VERSION 5.7 ;
  NOWIREEXTENSIONATPIN ON ;
  DIVIDERCHAR "/" ;
  BUSBITCHARS "[]" ;
MACRO sky130_fd_pr__cap_mim_m3_1_RRZ644
  CLASS BLOCK ;
  FOREIGN sky130_fd_pr__cap_mim_m3_1_RRZ644 ;
  ORIGIN 4.750 4.500 ;
  SIZE 9.000 BY 9.000 ;
  OBS
      LAYER met3 ;
        RECT -4.750 -4.500 4.250 4.500 ;
      LAYER met4 ;
        RECT -4.055 -3.805 3.555 3.805 ;
  END
END sky130_fd_pr__cap_mim_m3_1_RRZ644
MACRO sky130_fd_pr__cap_mim_m3_1_4CW8F2
  CLASS BLOCK ;
  FOREIGN sky130_fd_pr__cap_mim_m3_1_4CW8F2 ;
  ORIGIN 4.750 2.500 ;
  SIZE 9.000 BY 5.000 ;
  OBS
      LAYER met3 ;
        RECT -4.750 -2.500 4.250 2.500 ;
      LAYER met4 ;
        RECT -4.055 -1.805 3.555 1.805 ;
  END
END sky130_fd_pr__cap_mim_m3_1_4CW8F2
MACRO INV_B_13409687_0_1653520173
  CLASS BLOCK ;
  FOREIGN INV_B_13409687_0_1653520173 ;
  ORIGIN 0.000 0.000 ;
  SIZE 5.415 BY 7.560 ;
  OBS
      LAYER nwell ;
        RECT 0.000 0.000 3.440 7.560 ;
      LAYER pwell ;
        RECT 4.515 6.030 4.945 7.410 ;
        RECT 4.045 2.495 5.415 3.175 ;
      LAYER li1 ;
        RECT 1.165 6.215 1.415 7.225 ;
        RECT 2.025 6.215 2.275 7.225 ;
        RECT 4.605 6.215 4.855 7.225 ;
        RECT 1.165 4.115 1.415 5.125 ;
        RECT 2.025 4.115 2.275 5.125 ;
        RECT 4.605 4.115 4.855 5.125 ;
        RECT 0.735 0.335 0.985 3.865 ;
        RECT 1.165 0.335 1.415 3.865 ;
        RECT 1.595 0.335 1.845 3.865 ;
        RECT 2.025 0.335 2.275 3.865 ;
        RECT 2.455 0.335 2.705 3.865 ;
        RECT 4.175 0.335 4.425 3.865 ;
        RECT 4.605 0.335 4.855 3.865 ;
        RECT 5.035 0.335 5.285 3.865 ;
      LAYER mcon ;
        RECT 1.205 6.635 1.375 6.805 ;
        RECT 2.065 6.635 2.235 6.805 ;
        RECT 4.645 6.635 4.815 6.805 ;
        RECT 1.205 4.535 1.375 4.705 ;
        RECT 2.065 4.535 2.235 4.705 ;
        RECT 4.645 4.535 4.815 4.705 ;
        RECT 0.775 0.755 0.945 0.925 ;
        RECT 1.205 0.335 1.375 0.505 ;
        RECT 1.635 0.755 1.805 0.925 ;
        RECT 2.065 0.335 2.235 0.505 ;
        RECT 2.495 0.755 2.665 0.925 ;
        RECT 4.215 0.755 4.385 0.925 ;
        RECT 4.645 0.335 4.815 0.505 ;
        RECT 5.075 0.755 5.245 0.925 ;
      LAYER met1 ;
        RECT 1.120 6.580 2.320 6.860 ;
        RECT 4.130 6.580 5.330 6.860 ;
        RECT 1.120 4.480 4.900 4.760 ;
        RECT 0.690 0.700 2.750 0.980 ;
        RECT 4.130 0.700 5.330 0.980 ;
        RECT 1.120 0.280 4.900 0.560 ;
      LAYER via ;
        RECT 5.030 6.590 5.290 6.850 ;
        RECT 5.030 0.710 5.290 0.970 ;
      LAYER met2 ;
        RECT 5.020 0.680 5.300 6.880 ;
  END
END INV_B_13409687_0_1653520173
MACRO sky130_fd_pr__cap_mim_m3_1_F8PC2Z
  CLASS BLOCK ;
  FOREIGN sky130_fd_pr__cap_mim_m3_1_F8PC2Z ;
  ORIGIN 2.750 1.500 ;
  SIZE 5.000 BY 3.000 ;
  OBS
      LAYER met3 ;
        RECT -2.750 -1.500 2.250 1.500 ;
      LAYER met4 ;
        RECT -2.055 -0.805 1.555 0.805 ;
  END
END sky130_fd_pr__cap_mim_m3_1_F8PC2Z
MACRO sky130_fd_pr__cap_mim_m3_1_K8PL49$1
  CLASS BLOCK ;
  FOREIGN sky130_fd_pr__cap_mim_m3_1_K8PL49$1 ;
  ORIGIN 2.750 2.500 ;
  SIZE 5.000 BY 5.000 ;
  OBS
      LAYER met3 ;
        RECT -2.750 -2.500 2.250 2.500 ;
      LAYER met4 ;
        RECT -2.055 -1.805 1.555 1.805 ;
  END
END sky130_fd_pr__cap_mim_m3_1_K8PL49$1
MACRO sky130_fd_pr__cap_mim_m3_1_FJFAMD
  CLASS BLOCK ;
  FOREIGN sky130_fd_pr__cap_mim_m3_1_FJFAMD ;
  ORIGIN 1.750 1.500 ;
  SIZE 3.000 BY 3.000 ;
  OBS
      LAYER met3 ;
        RECT -1.750 -1.500 1.250 1.500 ;
      LAYER met4 ;
        RECT -1.055 -0.805 0.555 0.805 ;
  END
END sky130_fd_pr__cap_mim_m3_1_FJFAMD
MACRO sky130_fd_pr__cap_mim_m3_1_4VD94C$1
  CLASS BLOCK ;
  FOREIGN sky130_fd_pr__cap_mim_m3_1_4VD94C$1 ;
  ORIGIN 8.750 4.500 ;
  SIZE 17.000 BY 9.000 ;
  OBS
      LAYER met3 ;
        RECT -8.750 -4.500 8.250 4.500 ;
      LAYER met4 ;
        RECT -8.055 -3.805 7.555 3.805 ;
  END
END sky130_fd_pr__cap_mim_m3_1_4VD94C$1
MACRO NMOS_S_22639876_X1_Y1_1653520174
  CLASS BLOCK ;
  FOREIGN NMOS_S_22639876_X1_Y1_1653520174 ;
  ORIGIN 7.000 -0.280 ;
  SIZE 8.975 BY 7.130 ;
  OBS
      LAYER pwell ;
        RECT 1.075 6.030 1.505 7.410 ;
        RECT 0.605 2.495 1.975 3.175 ;
      LAYER li1 ;
        RECT 1.165 6.215 1.415 7.225 ;
        RECT 1.165 4.115 1.415 5.125 ;
        RECT 0.735 0.335 0.985 3.865 ;
        RECT 1.165 0.335 1.415 3.865 ;
        RECT 1.595 0.335 1.845 3.865 ;
      LAYER mcon ;
        RECT 1.205 6.635 1.375 6.805 ;
        RECT 1.205 4.535 1.375 4.705 ;
        RECT 0.775 0.755 0.945 0.925 ;
        RECT 1.205 0.335 1.375 0.505 ;
        RECT 1.635 0.755 1.805 0.925 ;
      LAYER met1 ;
        RECT 0.690 6.580 1.890 6.860 ;
        RECT -7.000 4.480 1.460 4.760 ;
        RECT 0.690 0.700 1.890 0.980 ;
        RECT 0.260 0.280 1.460 0.560 ;
      LAYER via ;
        RECT 1.590 6.590 1.850 6.850 ;
        RECT 1.590 0.710 1.850 0.970 ;
      LAYER met2 ;
        RECT 1.580 0.680 1.860 6.880 ;
  END
END NMOS_S_22639876_X1_Y1_1653520174
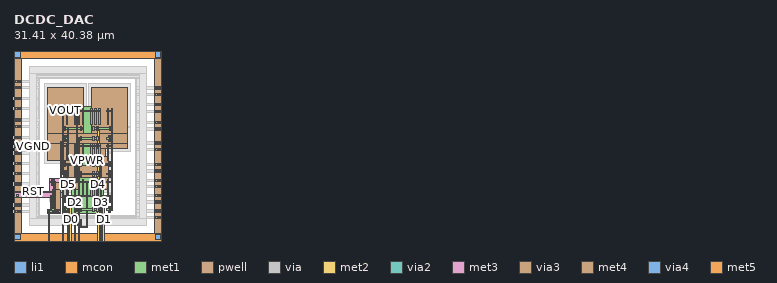
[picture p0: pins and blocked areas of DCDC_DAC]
MACRO DCDC_DAC
  CLASS BLOCK ;
  FOREIGN DCDC_DAC ;
  ORIGIN -0.080 -0.005 ;
  SIZE 31.410 BY 40.380 ;
  PIN RST
    ANTENNAGATEAREA 0.126000 ;
    PORT
      LAYER li1 ;
        RECT 8.245 9.960 8.495 10.970 ;
      LAYER mcon ;
        RECT 8.285 10.380 8.455 10.550 ;
      LAYER met1 ;
        RECT 0.080 10.325 8.540 10.605 ;
    END
  END RST
  PIN VGND
    USE GROUND ;
    PORT
      LAYER pwell ;
        RECT 10.735 21.115 11.165 22.495 ;
        RECT 20.195 21.115 20.625 22.495 ;
        RECT 10.735 13.555 11.165 14.935 ;
        RECT 20.195 13.555 20.625 14.935 ;
        RECT 8.155 11.875 8.585 13.255 ;
        RECT 10.735 5.995 11.165 7.375 ;
        RECT 20.195 5.995 20.625 7.375 ;
      LAYER li1 ;
        RECT 10.395 24.660 10.645 28.190 ;
        RECT 11.255 24.660 11.505 28.190 ;
        RECT 19.855 24.660 20.105 28.190 ;
        RECT 20.715 24.660 20.965 28.190 ;
        RECT 10.825 21.300 11.075 22.310 ;
        RECT 20.285 21.300 20.535 22.310 ;
        RECT 9.965 13.320 10.215 21.050 ;
        RECT 10.395 17.100 10.645 20.630 ;
        RECT 11.255 17.100 11.505 20.630 ;
        RECT 19.855 17.100 20.105 20.630 ;
        RECT 20.715 17.100 20.965 20.630 ;
        RECT 10.825 13.740 11.075 14.750 ;
        RECT 20.285 13.740 20.535 14.750 ;
        RECT 8.245 12.060 8.495 13.070 ;
        RECT 7.815 6.180 8.065 9.710 ;
        RECT 8.675 6.180 8.925 9.710 ;
        RECT 10.395 9.540 10.645 13.070 ;
        RECT 11.255 9.540 11.505 13.070 ;
        RECT 19.855 9.540 20.105 13.070 ;
        RECT 20.715 9.540 20.965 13.070 ;
        RECT 10.825 6.180 11.075 7.190 ;
        RECT 20.285 6.180 20.535 7.190 ;
      LAYER mcon ;
        RECT 10.435 27.600 10.605 27.770 ;
        RECT 11.295 27.600 11.465 27.770 ;
        RECT 19.895 27.600 20.065 27.770 ;
        RECT 20.755 27.600 20.925 27.770 ;
        RECT 10.865 21.720 11.035 21.890 ;
        RECT 20.325 21.720 20.495 21.890 ;
        RECT 10.005 20.880 10.175 21.050 ;
        RECT 10.005 17.100 10.175 17.270 ;
        RECT 10.435 20.040 10.605 20.210 ;
        RECT 11.295 20.040 11.465 20.210 ;
        RECT 19.895 20.040 20.065 20.210 ;
        RECT 20.755 20.040 20.925 20.210 ;
        RECT 10.865 14.160 11.035 14.330 ;
        RECT 20.325 14.160 20.495 14.330 ;
        RECT 10.005 13.320 10.175 13.490 ;
        RECT 8.285 12.480 8.455 12.650 ;
        RECT 10.435 12.480 10.605 12.650 ;
        RECT 7.855 6.600 8.025 6.770 ;
        RECT 11.295 12.480 11.465 12.650 ;
        RECT 19.895 12.480 20.065 12.650 ;
        RECT 20.755 12.480 20.925 12.650 ;
        RECT 8.715 6.600 8.885 6.770 ;
        RECT 10.865 6.600 11.035 6.770 ;
        RECT 20.325 6.600 20.495 6.770 ;
      LAYER met1 ;
        RECT 10.350 27.545 11.550 27.825 ;
        RECT 19.810 27.545 21.010 27.825 ;
        RECT 10.350 21.665 11.550 21.945 ;
        RECT 19.810 21.665 21.010 21.945 ;
        RECT 9.920 20.825 10.680 21.105 ;
        RECT 10.350 19.985 11.550 20.265 ;
        RECT 19.810 19.985 21.010 20.265 ;
        RECT 9.920 17.045 10.680 17.325 ;
        RECT 10.350 14.105 11.550 14.385 ;
        RECT 19.810 14.105 21.010 14.385 ;
        RECT 9.920 13.265 10.680 13.545 ;
        RECT 7.770 12.425 8.970 12.705 ;
        RECT 10.350 12.425 11.550 12.705 ;
        RECT 19.810 12.425 21.010 12.705 ;
        RECT 10.360 9.485 21.000 9.765 ;
        RECT 7.770 6.545 8.970 6.825 ;
        RECT 10.350 6.545 11.550 6.825 ;
        RECT 19.810 6.545 21.010 6.825 ;
      LAYER via ;
        RECT 10.390 27.555 10.650 27.815 ;
        RECT 20.710 27.555 20.970 27.815 ;
        RECT 10.390 21.675 10.650 21.935 ;
        RECT 20.710 21.675 20.970 21.935 ;
        RECT 10.390 20.835 10.650 21.095 ;
        RECT 10.390 19.995 10.650 20.255 ;
        RECT 20.710 19.995 20.970 20.255 ;
        RECT 10.390 17.055 10.650 17.315 ;
        RECT 10.390 14.115 10.650 14.375 ;
        RECT 20.710 14.115 20.970 14.375 ;
        RECT 10.390 13.275 10.650 13.535 ;
        RECT 8.670 12.435 8.930 12.695 ;
        RECT 10.390 12.435 10.650 12.695 ;
        RECT 20.710 12.435 20.970 12.695 ;
        RECT 10.390 9.495 10.650 9.755 ;
        RECT 20.710 9.495 20.970 9.755 ;
        RECT 8.670 6.555 8.930 6.815 ;
        RECT 10.390 6.555 10.650 6.815 ;
        RECT 20.710 6.555 20.970 6.815 ;
      LAYER met2 ;
        RECT 10.380 20.805 10.660 27.845 ;
        RECT 10.380 14.085 10.660 20.285 ;
        RECT 8.660 6.525 8.940 12.725 ;
        RECT 10.380 0.005 10.660 13.565 ;
        RECT 20.700 6.525 20.980 27.845 ;
      LAYER via2 ;
        RECT 8.660 9.485 8.940 9.765 ;
        RECT 10.380 9.485 10.660 9.765 ;
      LAYER met3 ;
        RECT 0.380 33.685 1.380 34.165 ;
        RECT 0.380 32.325 1.380 32.805 ;
        RECT 30.190 32.275 31.190 32.755 ;
        RECT 30.190 30.915 31.190 31.395 ;
        RECT 0.380 30.115 1.380 30.595 ;
        RECT 30.190 28.715 31.190 29.195 ;
        RECT 0.380 27.885 1.380 28.365 ;
        RECT 30.190 27.355 31.190 27.835 ;
        RECT 0.380 25.465 1.380 25.945 ;
        RECT 30.190 24.935 31.190 25.415 ;
        RECT 0.380 24.105 1.380 24.585 ;
        RECT 30.190 23.575 31.190 24.055 ;
        RECT 0.380 21.835 1.380 22.315 ;
        RECT 30.190 20.575 31.190 21.055 ;
        RECT 0.380 19.805 1.380 20.285 ;
        RECT 30.190 19.215 31.190 19.695 ;
        RECT 0.380 18.445 1.380 18.925 ;
        RECT 0.380 16.275 1.380 16.755 ;
        RECT 30.190 16.005 31.190 16.485 ;
        RECT 30.190 14.645 31.190 15.125 ;
        RECT 0.380 14.095 1.380 14.575 ;
        RECT 0.380 11.855 1.380 12.335 ;
        RECT 7.690 10.225 10.690 13.225 ;
        RECT 30.190 12.665 31.190 13.145 ;
        RECT 30.190 11.305 31.190 11.785 ;
        RECT 0.080 9.225 10.690 10.225 ;
        RECT 30.190 9.415 31.190 9.895 ;
        RECT 30.190 8.055 31.190 8.535 ;
        RECT 0.380 7.395 1.380 7.875 ;
        RECT 0.380 6.035 1.380 6.515 ;
        RECT 30.190 6.115 31.190 6.595 ;
        RECT 30.190 4.755 31.190 5.235 ;
      LAYER via3 ;
        RECT 0.490 33.770 0.810 34.090 ;
        RECT 1.010 33.770 1.330 34.090 ;
        RECT 0.490 32.410 0.810 32.730 ;
        RECT 1.010 32.410 1.330 32.730 ;
        RECT 30.240 32.360 30.560 32.680 ;
        RECT 30.760 32.360 31.080 32.680 ;
        RECT 30.240 31.000 30.560 31.320 ;
        RECT 30.760 31.000 31.080 31.320 ;
        RECT 0.490 30.200 0.810 30.520 ;
        RECT 1.010 30.200 1.330 30.520 ;
        RECT 30.240 28.800 30.560 29.120 ;
        RECT 30.760 28.800 31.080 29.120 ;
        RECT 0.490 27.970 0.810 28.290 ;
        RECT 1.010 27.970 1.330 28.290 ;
        RECT 30.240 27.440 30.560 27.760 ;
        RECT 30.760 27.440 31.080 27.760 ;
        RECT 0.490 25.550 0.810 25.870 ;
        RECT 1.010 25.550 1.330 25.870 ;
        RECT 30.240 25.020 30.560 25.340 ;
        RECT 30.760 25.020 31.080 25.340 ;
        RECT 0.490 24.190 0.810 24.510 ;
        RECT 1.010 24.190 1.330 24.510 ;
        RECT 30.240 23.660 30.560 23.980 ;
        RECT 30.760 23.660 31.080 23.980 ;
        RECT 0.490 21.920 0.810 22.240 ;
        RECT 1.010 21.920 1.330 22.240 ;
        RECT 30.240 20.660 30.560 20.980 ;
        RECT 30.760 20.660 31.080 20.980 ;
        RECT 0.490 19.880 0.810 20.200 ;
        RECT 1.010 19.880 1.330 20.200 ;
        RECT 30.240 19.300 30.560 19.620 ;
        RECT 30.760 19.300 31.080 19.620 ;
        RECT 0.490 18.520 0.810 18.840 ;
        RECT 1.010 18.520 1.330 18.840 ;
        RECT 0.490 16.360 0.810 16.680 ;
        RECT 1.010 16.360 1.330 16.680 ;
        RECT 30.240 16.090 30.560 16.410 ;
        RECT 30.760 16.090 31.080 16.410 ;
        RECT 30.240 14.730 30.560 15.050 ;
        RECT 30.760 14.730 31.080 15.050 ;
        RECT 0.490 14.180 0.810 14.500 ;
        RECT 1.010 14.180 1.330 14.500 ;
        RECT 0.490 11.940 0.810 12.260 ;
        RECT 1.010 11.940 1.330 12.260 ;
        RECT 30.240 12.750 30.560 13.070 ;
        RECT 30.760 12.750 31.080 13.070 ;
        RECT 30.240 11.390 30.560 11.710 ;
        RECT 30.760 11.390 31.080 11.710 ;
        RECT 0.620 9.470 1.140 9.990 ;
        RECT 30.240 9.500 30.560 9.820 ;
        RECT 30.760 9.500 31.080 9.820 ;
        RECT 30.240 8.140 30.560 8.460 ;
        RECT 30.760 8.140 31.080 8.460 ;
        RECT 0.490 7.480 0.810 7.800 ;
        RECT 1.010 7.480 1.330 7.800 ;
        RECT 0.490 6.120 0.810 6.440 ;
        RECT 1.010 6.120 1.330 6.440 ;
        RECT 30.240 6.200 30.560 6.520 ;
        RECT 30.760 6.200 31.080 6.520 ;
        RECT 30.240 4.840 30.560 5.160 ;
        RECT 30.760 4.840 31.080 5.160 ;
      LAYER met4 ;
        RECT 0.080 0.005 1.680 40.385 ;
        RECT 29.890 0.005 31.490 40.385 ;
      LAYER via4 ;
        RECT 0.285 39.005 1.465 40.185 ;
        RECT 0.285 0.225 1.465 1.405 ;
        RECT 30.105 39.005 31.285 40.185 ;
        RECT 30.105 0.225 31.285 1.405 ;
      LAYER met5 ;
        RECT 0.080 38.785 31.490 40.385 ;
        RECT 0.080 0.005 31.490 1.605 ;
    END
  END VGND
  PIN VPWR
    USE POWER ;
    PORT
      LAYER nwell ;
        RECT 12.240 5.845 19.120 28.525 ;
      LAYER li1 ;
        RECT 12.975 24.660 13.225 28.190 ;
        RECT 13.835 24.660 14.085 28.190 ;
        RECT 14.695 24.660 14.945 28.190 ;
        RECT 16.415 24.660 16.665 28.190 ;
        RECT 17.275 24.660 17.525 28.190 ;
        RECT 18.135 24.660 18.385 28.190 ;
        RECT 13.405 21.300 13.655 22.310 ;
        RECT 14.265 21.300 14.515 22.310 ;
        RECT 16.845 21.300 17.095 22.310 ;
        RECT 17.705 21.300 17.955 22.310 ;
        RECT 12.975 17.100 13.225 20.630 ;
        RECT 13.835 17.100 14.085 20.630 ;
        RECT 14.695 17.100 14.945 20.630 ;
        RECT 16.415 17.100 16.665 20.630 ;
        RECT 17.275 17.100 17.525 20.630 ;
        RECT 18.135 17.100 18.385 20.630 ;
        RECT 13.405 13.740 13.655 14.750 ;
        RECT 14.265 13.740 14.515 14.750 ;
        RECT 16.845 13.740 17.095 14.750 ;
        RECT 17.705 13.740 17.955 14.750 ;
        RECT 12.975 9.540 13.225 13.070 ;
        RECT 13.835 9.540 14.085 13.070 ;
        RECT 14.695 9.540 14.945 13.070 ;
        RECT 16.415 9.540 16.665 13.070 ;
        RECT 17.275 9.540 17.525 13.070 ;
        RECT 18.135 9.540 18.385 13.070 ;
        RECT 13.405 6.180 13.655 7.190 ;
        RECT 14.265 6.180 14.515 7.190 ;
        RECT 16.845 6.180 17.095 7.190 ;
        RECT 17.705 6.180 17.955 7.190 ;
      LAYER mcon ;
        RECT 13.015 27.600 13.185 27.770 ;
        RECT 13.875 27.600 14.045 27.770 ;
        RECT 14.735 27.600 14.905 27.770 ;
        RECT 16.455 27.600 16.625 27.770 ;
        RECT 17.315 27.600 17.485 27.770 ;
        RECT 18.175 27.600 18.345 27.770 ;
        RECT 13.445 21.720 13.615 21.890 ;
        RECT 14.305 21.720 14.475 21.890 ;
        RECT 16.885 21.720 17.055 21.890 ;
        RECT 17.745 21.720 17.915 21.890 ;
        RECT 13.015 20.040 13.185 20.210 ;
        RECT 13.875 20.040 14.045 20.210 ;
        RECT 14.735 20.040 14.905 20.210 ;
        RECT 16.455 20.040 16.625 20.210 ;
        RECT 17.315 20.040 17.485 20.210 ;
        RECT 18.175 20.040 18.345 20.210 ;
        RECT 13.445 14.160 13.615 14.330 ;
        RECT 14.305 14.160 14.475 14.330 ;
        RECT 16.885 14.160 17.055 14.330 ;
        RECT 17.745 14.160 17.915 14.330 ;
        RECT 13.015 12.480 13.185 12.650 ;
        RECT 13.875 12.480 14.045 12.650 ;
        RECT 14.735 12.480 14.905 12.650 ;
        RECT 16.455 12.480 16.625 12.650 ;
        RECT 17.315 12.480 17.485 12.650 ;
        RECT 18.175 12.480 18.345 12.650 ;
        RECT 13.445 6.600 13.615 6.770 ;
        RECT 14.305 6.600 14.475 6.770 ;
        RECT 16.885 6.600 17.055 6.770 ;
        RECT 17.745 6.600 17.915 6.770 ;
      LAYER met1 ;
        RECT 12.930 27.545 18.430 27.825 ;
        RECT 13.360 21.665 18.000 21.945 ;
        RECT 12.930 19.985 18.430 20.265 ;
        RECT 13.360 14.105 18.000 14.385 ;
        RECT 12.930 12.425 18.430 12.705 ;
        RECT 13.360 6.545 18.000 6.825 ;
      LAYER via ;
        RECT 13.400 27.555 13.660 27.815 ;
        RECT 13.830 21.675 14.090 21.935 ;
        RECT 13.400 19.995 13.660 20.255 ;
        RECT 13.830 14.115 14.090 14.375 ;
        RECT 13.400 12.435 13.660 12.695 ;
        RECT 15.410 12.435 15.670 12.695 ;
        RECT 13.830 6.555 14.090 6.815 ;
      LAYER met2 ;
        RECT 13.390 12.405 13.670 27.845 ;
        RECT 13.820 3.155 14.100 21.965 ;
        RECT 15.400 3.155 15.680 12.750 ;
        RECT 13.820 2.910 15.680 3.155 ;
        RECT 13.820 0.005 14.100 2.910 ;
      LAYER via2 ;
        RECT 13.820 4.135 14.100 4.415 ;
        RECT 13.820 3.725 14.100 4.005 ;
      LAYER met3 ;
        RECT 13.520 3.205 14.470 4.615 ;
      LAYER via3 ;
        RECT 13.800 4.070 14.120 4.390 ;
        RECT 13.800 3.660 14.120 3.980 ;
      LAYER met4 ;
        RECT 13.720 3.505 14.200 4.505 ;
    END
  END VPWR
  PIN D0
    ANTENNAGATEAREA 0.378000 ;
    PORT
      LAYER li1 ;
        RECT 10.825 8.280 11.075 9.290 ;
        RECT 13.405 8.280 13.655 9.290 ;
        RECT 14.265 8.280 14.515 9.290 ;
      LAYER mcon ;
        RECT 10.865 8.700 11.035 8.870 ;
        RECT 13.445 8.700 13.615 8.870 ;
        RECT 14.305 8.700 14.475 8.870 ;
      LAYER met1 ;
        RECT 10.780 8.645 14.560 8.925 ;
      LAYER via ;
        RECT 11.990 8.655 12.250 8.915 ;
      LAYER met2 ;
        RECT 11.980 0.005 12.260 8.945 ;
    END
  END D0
  PIN D2
    ANTENNAGATEAREA 0.378000 ;
    PORT
      LAYER li1 ;
        RECT 10.825 15.840 11.075 16.850 ;
        RECT 13.405 15.840 13.655 16.850 ;
        RECT 14.265 15.840 14.515 16.850 ;
      LAYER mcon ;
        RECT 10.865 16.260 11.035 16.430 ;
        RECT 13.445 16.260 13.615 16.430 ;
        RECT 14.305 16.260 14.475 16.430 ;
      LAYER met1 ;
        RECT 10.780 16.205 14.560 16.485 ;
      LAYER via ;
        RECT 12.850 16.215 13.110 16.475 ;
      LAYER met2 ;
        RECT 12.840 0.005 13.120 16.505 ;
    END
  END D2
  PIN D5
    ANTENNAGATEAREA 0.378000 ;
    PORT
      LAYER li1 ;
        RECT 10.825 23.400 11.075 24.410 ;
        RECT 13.405 23.400 13.655 24.410 ;
        RECT 14.265 23.400 14.515 24.410 ;
      LAYER mcon ;
        RECT 10.865 23.820 11.035 23.990 ;
        RECT 13.445 23.820 13.615 23.990 ;
        RECT 14.305 23.820 14.475 23.990 ;
      LAYER met1 ;
        RECT 10.780 23.765 14.560 24.045 ;
      LAYER via ;
        RECT 11.430 23.775 11.690 24.035 ;
      LAYER met2 ;
        RECT 11.420 0.005 11.700 24.065 ;
    END
  END D5
  PIN D3
    ANTENNAGATEAREA 0.378000 ;
    PORT
      LAYER li1 ;
        RECT 16.845 15.840 17.095 16.850 ;
        RECT 17.705 15.840 17.955 16.850 ;
        RECT 20.285 15.840 20.535 16.850 ;
      LAYER mcon ;
        RECT 16.885 16.260 17.055 16.430 ;
        RECT 17.745 16.260 17.915 16.430 ;
        RECT 20.325 16.260 20.495 16.430 ;
      LAYER met1 ;
        RECT 16.800 16.205 20.580 16.485 ;
      LAYER via ;
        RECT 18.440 16.215 18.700 16.475 ;
      LAYER met2 ;
        RECT 18.430 0.005 18.710 16.505 ;
    END
  END D3
  PIN D4
    ANTENNAGATEAREA 0.378000 ;
    PORT
      LAYER li1 ;
        RECT 16.845 23.400 17.095 24.410 ;
        RECT 17.705 23.400 17.955 24.410 ;
        RECT 20.285 23.400 20.535 24.410 ;
      LAYER mcon ;
        RECT 16.885 23.820 17.055 23.990 ;
        RECT 17.745 23.820 17.915 23.990 ;
        RECT 20.325 23.820 20.495 23.990 ;
      LAYER met1 ;
        RECT 16.800 23.765 20.580 24.045 ;
      LAYER via ;
        RECT 17.880 23.775 18.140 24.035 ;
      LAYER met2 ;
        RECT 17.870 0.005 18.150 24.065 ;
    END
  END D4
  PIN D1
    ANTENNAGATEAREA 0.378000 ;
    PORT
      LAYER li1 ;
        RECT 16.845 8.280 17.095 9.290 ;
        RECT 17.705 8.280 17.955 9.290 ;
        RECT 20.285 8.280 20.535 9.290 ;
      LAYER mcon ;
        RECT 16.885 8.700 17.055 8.870 ;
        RECT 17.745 8.700 17.915 8.870 ;
        RECT 20.325 8.700 20.495 8.870 ;
      LAYER met1 ;
        RECT 16.800 8.645 20.580 8.925 ;
      LAYER via ;
        RECT 19.000 8.655 19.260 8.915 ;
      LAYER met2 ;
        RECT 18.990 0.005 19.270 8.945 ;
    END
  END D1
  PIN VOUT
    ANTENNADIFFAREA 0.117600 ;
    PORT
      LAYER li1 ;
        RECT 8.245 6.180 8.495 9.710 ;
      LAYER mcon ;
        RECT 8.285 6.180 8.455 6.350 ;
      LAYER met1 ;
        RECT 7.340 6.125 8.540 6.405 ;
      LAYER via ;
        RECT 7.370 6.135 7.630 6.395 ;
      LAYER met2 ;
        RECT 7.360 0.000 7.640 6.450 ;
      LAYER via2 ;
        RECT 7.360 6.125 7.640 6.405 ;
      LAYER met3 ;
        RECT 7.280 5.845 10.000 6.645 ;
      LAYER via3 ;
        RECT 8.425 6.085 8.745 6.405 ;
        RECT 8.825 6.085 9.145 6.405 ;
        RECT 9.225 6.085 9.545 6.405 ;
        RECT 9.625 6.085 9.945 6.405 ;
      LAYER met4 ;
        RECT 7.175 22.865 14.785 32.730 ;
        RECT 16.575 22.865 24.185 32.730 ;
        RECT 7.175 20.775 24.185 22.865 ;
        RECT 7.175 17.120 14.785 20.775 ;
        RECT 16.575 19.720 24.185 20.775 ;
        RECT 17.280 17.930 19.480 19.720 ;
        RECT 10.670 15.945 13.310 17.120 ;
        RECT 16.575 15.945 20.185 17.930 ;
        RECT 10.670 13.545 20.185 15.945 ;
        RECT 10.670 12.530 13.310 13.545 ;
        RECT 8.385 10.945 13.895 12.530 ;
        RECT 8.380 10.920 13.895 10.945 ;
        RECT 16.575 10.920 20.185 13.545 ;
        RECT 8.380 5.845 10.000 10.920 ;
    END
  END VOUT
  OBS
      LAYER pwell ;
        RECT 4.650 34.475 26.810 35.335 ;
        RECT 4.650 5.405 5.510 34.475 ;
        RECT 10.265 25.350 11.635 26.030 ;
        RECT 19.725 25.350 21.095 26.030 ;
        RECT 10.265 17.790 11.635 18.470 ;
        RECT 19.725 17.790 21.095 18.470 ;
        RECT 10.265 10.230 11.635 10.910 ;
        RECT 19.725 10.230 21.095 10.910 ;
        RECT 7.685 8.340 9.055 9.020 ;
        RECT 25.950 5.405 26.810 34.475 ;
        RECT 4.650 4.545 26.810 5.405 ;
      LAYER li1 ;
        RECT 4.785 34.850 26.675 35.205 ;
        RECT 4.780 34.605 26.680 34.850 ;
        RECT 4.780 5.275 5.380 34.605 ;
        RECT 10.825 24.660 11.075 28.190 ;
        RECT 13.405 24.660 13.655 28.190 ;
        RECT 14.265 24.660 14.515 28.190 ;
        RECT 16.845 24.660 17.095 28.190 ;
        RECT 17.705 24.660 17.955 28.190 ;
        RECT 20.285 24.660 20.535 28.190 ;
        RECT 10.825 17.100 11.075 20.630 ;
        RECT 13.405 17.100 13.655 20.630 ;
        RECT 14.265 17.100 14.515 20.630 ;
        RECT 16.845 17.100 17.095 20.630 ;
        RECT 17.705 17.100 17.955 20.630 ;
        RECT 20.285 17.100 20.535 20.630 ;
        RECT 10.825 9.540 11.075 13.070 ;
        RECT 13.405 9.540 13.655 13.070 ;
        RECT 14.265 9.540 14.515 13.070 ;
        RECT 16.845 9.540 17.095 13.070 ;
        RECT 17.705 9.540 17.955 13.070 ;
        RECT 20.285 9.540 20.535 13.070 ;
        RECT 26.080 5.275 26.680 34.605 ;
        RECT 4.780 4.910 26.680 5.275 ;
        RECT 4.785 4.675 26.675 4.910 ;
      LAYER mcon ;
        RECT 5.095 33.850 5.265 34.020 ;
        RECT 5.095 32.490 5.265 32.660 ;
        RECT 5.095 30.280 5.265 30.450 ;
        RECT 5.095 28.050 5.265 28.220 ;
        RECT 26.295 32.440 26.465 32.610 ;
        RECT 26.295 31.080 26.465 31.250 ;
        RECT 26.295 28.880 26.465 29.050 ;
        RECT 5.095 25.630 5.265 25.800 ;
        RECT 10.865 28.020 11.035 28.190 ;
        RECT 13.445 28.020 13.615 28.190 ;
        RECT 14.305 28.020 14.475 28.190 ;
        RECT 16.885 28.020 17.055 28.190 ;
        RECT 17.745 28.020 17.915 28.190 ;
        RECT 20.325 28.020 20.495 28.190 ;
        RECT 26.295 27.520 26.465 27.690 ;
        RECT 26.295 25.100 26.465 25.270 ;
        RECT 5.095 24.270 5.265 24.440 ;
        RECT 5.095 22.000 5.265 22.170 ;
        RECT 26.295 23.740 26.465 23.910 ;
        RECT 26.295 20.740 26.465 20.910 ;
        RECT 5.095 19.950 5.265 20.140 ;
        RECT 5.095 18.590 5.265 18.780 ;
        RECT 10.865 20.460 11.035 20.630 ;
        RECT 13.445 20.460 13.615 20.630 ;
        RECT 14.305 20.460 14.475 20.630 ;
        RECT 16.885 20.460 17.055 20.630 ;
        RECT 17.745 20.460 17.915 20.630 ;
        RECT 20.325 20.460 20.495 20.630 ;
        RECT 26.295 19.380 26.465 19.550 ;
        RECT 5.095 16.440 5.265 16.610 ;
        RECT 5.095 14.260 5.265 14.430 ;
        RECT 26.295 16.170 26.465 16.340 ;
        RECT 26.295 14.810 26.465 14.980 ;
        RECT 5.095 12.020 5.265 12.190 ;
        RECT 10.865 12.900 11.035 13.070 ;
        RECT 13.445 12.900 13.615 13.070 ;
        RECT 14.305 12.900 14.475 13.070 ;
        RECT 16.885 12.900 17.055 13.070 ;
        RECT 17.745 12.900 17.915 13.070 ;
        RECT 20.325 12.900 20.495 13.070 ;
        RECT 26.295 12.830 26.465 13.000 ;
        RECT 26.295 11.470 26.465 11.640 ;
        RECT 26.295 9.580 26.465 9.750 ;
        RECT 5.095 7.560 5.265 7.730 ;
        RECT 5.095 6.200 5.265 6.370 ;
        RECT 26.295 8.220 26.465 8.390 ;
        RECT 26.295 6.280 26.465 6.450 ;
        RECT 26.295 4.920 26.465 5.090 ;
      LAYER met1 ;
        RECT 0.080 33.685 5.440 34.165 ;
        RECT 0.080 32.325 5.440 32.805 ;
        RECT 26.080 32.285 31.490 32.755 ;
        RECT 26.080 30.925 31.490 31.395 ;
        RECT 0.000 30.115 5.360 30.595 ;
        RECT 26.080 28.725 31.490 29.195 ;
        RECT 0.000 27.885 5.360 28.365 ;
        RECT 10.780 27.965 14.560 28.245 ;
        RECT 16.800 27.965 20.580 28.245 ;
        RECT 26.080 27.365 31.490 27.835 ;
        RECT 0.080 25.465 5.440 25.945 ;
        RECT 26.080 24.945 31.490 25.415 ;
        RECT 0.080 24.105 5.440 24.585 ;
        RECT 26.080 23.585 31.490 24.055 ;
        RECT 0.000 21.835 5.360 22.315 ;
        RECT 10.780 20.405 14.560 20.685 ;
        RECT 16.800 20.405 20.580 20.685 ;
        RECT 26.080 20.585 31.490 21.055 ;
        RECT 0.000 19.805 5.360 20.285 ;
        RECT 19.150 19.025 19.430 20.405 ;
        RECT 26.080 19.225 31.490 19.695 ;
        RECT 0.000 18.445 5.360 18.925 ;
        RECT 0.000 16.275 5.360 16.755 ;
        RECT 26.080 16.015 31.490 16.485 ;
        RECT 12.180 15.445 16.380 15.715 ;
        RECT 26.080 14.655 31.490 15.125 ;
        RECT 0.000 14.095 5.360 14.575 ;
        RECT 12.260 13.125 12.580 13.225 ;
        RECT 19.120 13.125 19.440 13.225 ;
        RECT 10.780 12.845 14.560 13.125 ;
        RECT 16.800 12.845 20.580 13.125 ;
        RECT 12.260 12.745 12.580 12.845 ;
        RECT 19.120 12.745 19.440 12.845 ;
        RECT 26.080 12.675 31.490 13.145 ;
        RECT 0.000 11.855 5.360 12.335 ;
        RECT 26.080 11.315 31.490 11.785 ;
        RECT 26.080 9.425 31.490 9.895 ;
        RECT 26.080 8.065 31.490 8.535 ;
        RECT 0.000 7.395 5.360 7.875 ;
        RECT 0.000 6.035 5.360 6.515 ;
        RECT 26.080 6.125 31.490 6.595 ;
        RECT 26.080 4.765 31.490 5.235 ;
      LAYER via ;
        RECT 0.440 33.795 0.700 34.055 ;
        RECT 1.040 33.795 1.300 34.055 ;
        RECT 0.440 32.435 0.700 32.695 ;
        RECT 1.040 32.435 1.300 32.695 ;
        RECT 30.270 32.385 30.530 32.645 ;
        RECT 30.870 32.385 31.130 32.645 ;
        RECT 30.270 31.025 30.530 31.285 ;
        RECT 30.870 31.025 31.130 31.285 ;
        RECT 0.440 30.225 0.700 30.485 ;
        RECT 1.040 30.225 1.300 30.485 ;
        RECT 30.270 28.825 30.530 29.085 ;
        RECT 30.870 28.825 31.130 29.085 ;
        RECT 0.440 27.995 0.700 28.255 ;
        RECT 1.040 27.995 1.300 28.255 ;
        RECT 12.350 27.975 12.610 28.235 ;
        RECT 19.150 27.975 19.410 28.235 ;
        RECT 30.270 27.465 30.530 27.725 ;
        RECT 30.870 27.465 31.130 27.725 ;
        RECT 0.440 25.575 0.700 25.835 ;
        RECT 1.040 25.575 1.300 25.835 ;
        RECT 30.270 25.045 30.530 25.305 ;
        RECT 30.870 25.045 31.130 25.305 ;
        RECT 0.440 24.215 0.700 24.475 ;
        RECT 1.040 24.215 1.300 24.475 ;
        RECT 30.270 23.685 30.530 23.945 ;
        RECT 30.870 23.685 31.130 23.945 ;
        RECT 0.440 21.945 0.700 22.205 ;
        RECT 1.040 21.945 1.300 22.205 ;
        RECT 30.270 20.685 30.530 20.945 ;
        RECT 30.870 20.685 31.130 20.945 ;
        RECT 12.290 20.415 12.550 20.675 ;
        RECT 0.440 19.915 0.700 20.175 ;
        RECT 1.040 19.915 1.300 20.175 ;
        RECT 19.160 19.085 19.420 19.345 ;
        RECT 30.270 19.325 30.530 19.585 ;
        RECT 30.870 19.325 31.130 19.585 ;
        RECT 0.440 18.555 0.700 18.815 ;
        RECT 1.040 18.555 1.300 18.815 ;
        RECT 0.440 16.385 0.700 16.645 ;
        RECT 1.040 16.385 1.300 16.645 ;
        RECT 30.270 16.115 30.530 16.375 ;
        RECT 30.870 16.115 31.130 16.375 ;
        RECT 12.290 15.455 12.550 15.715 ;
        RECT 15.920 15.445 16.180 15.705 ;
        RECT 30.270 14.755 30.530 15.015 ;
        RECT 30.870 14.755 31.130 15.015 ;
        RECT 0.440 14.205 0.700 14.465 ;
        RECT 1.040 14.205 1.300 14.465 ;
        RECT 12.280 12.845 12.540 13.105 ;
        RECT 19.150 12.855 19.410 13.115 ;
        RECT 30.270 12.775 30.530 13.035 ;
        RECT 30.870 12.775 31.130 13.035 ;
        RECT 0.440 11.965 0.700 12.225 ;
        RECT 1.040 11.965 1.300 12.225 ;
        RECT 30.270 11.415 30.530 11.675 ;
        RECT 30.870 11.415 31.130 11.675 ;
        RECT 30.270 9.525 30.530 9.785 ;
        RECT 30.870 9.525 31.130 9.785 ;
        RECT 30.270 8.165 30.530 8.425 ;
        RECT 30.870 8.165 31.130 8.425 ;
        RECT 0.440 7.505 0.700 7.765 ;
        RECT 1.040 7.505 1.300 7.765 ;
        RECT 0.440 6.145 0.700 6.405 ;
        RECT 1.040 6.145 1.300 6.405 ;
        RECT 30.270 6.225 30.530 6.485 ;
        RECT 30.870 6.225 31.130 6.485 ;
        RECT 30.270 4.865 30.530 5.125 ;
        RECT 30.870 4.865 31.130 5.125 ;
      LAYER met2 ;
        RECT 0.380 33.685 1.380 34.165 ;
        RECT 0.380 32.325 1.380 32.805 ;
        RECT 0.380 30.115 1.380 30.595 ;
        RECT 0.380 27.885 1.380 28.365 ;
        RECT 12.340 27.920 12.620 33.425 ;
        RECT 19.140 27.920 19.420 33.425 ;
        RECT 30.190 32.275 31.190 32.755 ;
        RECT 30.190 30.915 31.190 31.395 ;
        RECT 30.190 28.715 31.190 29.195 ;
        RECT 30.190 27.355 31.190 27.835 ;
        RECT 0.380 25.465 1.380 25.945 ;
        RECT 30.190 24.935 31.190 25.415 ;
        RECT 0.380 24.105 1.380 24.585 ;
        RECT 30.190 23.575 31.190 24.055 ;
        RECT 0.380 21.835 1.380 22.315 ;
        RECT 0.380 19.805 1.380 20.285 ;
        RECT 0.380 18.445 1.380 18.925 ;
        RECT 0.380 16.275 1.380 16.755 ;
        RECT 12.280 15.345 12.560 20.730 ;
        RECT 30.190 20.575 31.190 21.055 ;
        RECT 19.150 19.030 19.430 19.400 ;
        RECT 30.190 19.215 31.190 19.695 ;
        RECT 30.190 16.005 31.190 16.485 ;
        RECT 15.910 15.390 16.190 15.760 ;
        RECT 30.190 14.645 31.190 15.125 ;
        RECT 0.380 14.095 1.380 14.575 ;
        RECT 12.280 12.800 12.560 13.170 ;
        RECT 19.140 12.800 19.420 13.170 ;
        RECT 30.190 12.665 31.190 13.145 ;
        RECT 0.380 11.855 1.380 12.335 ;
        RECT 30.190 11.305 31.190 11.785 ;
        RECT 30.190 9.415 31.190 9.895 ;
        RECT 30.190 8.055 31.190 8.535 ;
        RECT 0.380 7.395 1.380 7.875 ;
        RECT 0.380 6.035 1.380 6.515 ;
        RECT 30.190 6.115 31.190 6.595 ;
        RECT 30.190 4.755 31.190 5.235 ;
      LAYER via2 ;
        RECT 12.340 33.045 12.620 33.325 ;
        RECT 19.140 33.045 19.420 33.325 ;
        RECT 19.150 19.075 19.430 19.355 ;
        RECT 15.910 15.435 16.190 15.715 ;
        RECT 12.280 12.845 12.560 13.125 ;
        RECT 19.140 12.845 19.420 13.125 ;
      LAYER met3 ;
        RECT 6.480 16.425 15.480 33.425 ;
        RECT 15.880 24.425 24.880 33.425 ;
        RECT 15.880 19.025 24.880 24.025 ;
        RECT 15.880 13.625 20.880 18.625 ;
        RECT 11.590 10.225 14.590 13.225 ;
        RECT 15.880 10.225 20.880 13.225 ;
      LAYER met4 ;
        RECT 3.280 3.205 4.880 37.185 ;
        RECT 26.680 3.205 28.280 37.185 ;
      LAYER via4 ;
        RECT 3.485 35.805 4.665 36.985 ;
        RECT 3.485 3.425 4.665 4.605 ;
        RECT 26.885 35.805 28.065 36.985 ;
        RECT 26.885 3.425 28.065 4.605 ;
      LAYER met5 ;
        RECT 3.280 35.585 28.280 37.185 ;
        RECT 3.280 3.205 28.280 4.805 ;
  END
END DCDC_DAC
END LIBRARY
